VERSION 5.8 ;
BUSBITCHARS "[]" ;
DIVIDERCHAR "/" ;

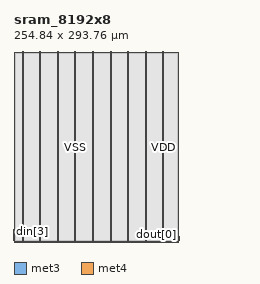
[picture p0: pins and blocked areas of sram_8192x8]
MACRO sram_8192x8
  CLASS BLOCK ;
  ORIGIN 0 0 ;
  SIZE 254.840 BY 293.760 ;
  SYMMETRY X Y ;

  PIN clk
    DIRECTION INPUT ;
    USE CLOCK ;
    PORT
      LAYER met3 ;
        RECT -0.500 2.890 0.500 3.230 ;
    END
  END clk

  PIN ce
    DIRECTION INPUT ;
    USE SIGNAL ;
    PORT
      LAYER met3 ;
        RECT -0.500 3.570 0.500 3.910 ;
    END
  END ce

  PIN we
    DIRECTION INPUT ;
    USE SIGNAL ;
    PORT
      LAYER met3 ;
        RECT -0.500 4.250 0.500 4.590 ;
    END
  END we

  PIN addr[0]
    DIRECTION INPUT ;
    USE SIGNAL ;
    PORT
      LAYER met3 ;
        RECT -0.500 4.930 0.500 5.270 ;
    END
  END addr[0]

  PIN addr[1]
    DIRECTION INPUT ;
    USE SIGNAL ;
    PORT
      LAYER met3 ;
        RECT -0.500 5.610 0.500 5.950 ;
    END
  END addr[1]

  PIN addr[2]
    DIRECTION INPUT ;
    USE SIGNAL ;
    PORT
      LAYER met3 ;
        RECT -0.500 6.290 0.500 6.630 ;
    END
  END addr[2]

  PIN addr[3]
    DIRECTION INPUT ;
    USE SIGNAL ;
    PORT
      LAYER met3 ;
        RECT -0.500 6.970 0.500 7.310 ;
    END
  END addr[3]

  PIN addr[4]
    DIRECTION INPUT ;
    USE SIGNAL ;
    PORT
      LAYER met3 ;
        RECT -0.500 7.650 0.500 7.990 ;
    END
  END addr[4]

  PIN addr[5]
    DIRECTION INPUT ;
    USE SIGNAL ;
    PORT
      LAYER met3 ;
        RECT -0.500 8.330 0.500 8.670 ;
    END
  END addr[5]

  PIN addr[6]
    DIRECTION INPUT ;
    USE SIGNAL ;
    PORT
      LAYER met3 ;
        RECT -0.500 9.010 0.500 9.350 ;
    END
  END addr[6]

  PIN addr[7]
    DIRECTION INPUT ;
    USE SIGNAL ;
    PORT
      LAYER met3 ;
        RECT -0.500 9.690 0.500 10.030 ;
    END
  END addr[7]

  PIN addr[8]
    DIRECTION INPUT ;
    USE SIGNAL ;
    PORT
      LAYER met3 ;
        RECT -0.500 10.370 0.500 10.710 ;
    END
  END addr[8]

  PIN addr[9]
    DIRECTION INPUT ;
    USE SIGNAL ;
    PORT
      LAYER met3 ;
        RECT -0.500 11.050 0.500 11.390 ;
    END
  END addr[9]

  PIN addr[10]
    DIRECTION INPUT ;
    USE SIGNAL ;
    PORT
      LAYER met3 ;
        RECT -0.500 11.730 0.500 12.070 ;
    END
  END addr[10]

  PIN addr[11]
    DIRECTION INPUT ;
    USE SIGNAL ;
    PORT
      LAYER met3 ;
        RECT -0.500 12.410 0.500 12.750 ;
    END
  END addr[11]

  PIN addr[12]
    DIRECTION INPUT ;
    USE SIGNAL ;
    PORT
      LAYER met3 ;
        RECT -0.500 13.090 0.500 13.430 ;
    END
  END addr[12]

  PIN din[0]
    DIRECTION INPUT ;
    USE SIGNAL ;
    PORT
      LAYER met3 ;
        RECT -0.500 13.770 0.500 14.110 ;
    END
  END din[0]

  PIN din[1]
    DIRECTION INPUT ;
    USE SIGNAL ;
    PORT
      LAYER met3 ;
        RECT -0.500 14.450 0.500 14.790 ;
    END
  END din[1]

  PIN din[2]
    DIRECTION INPUT ;
    USE SIGNAL ;
    PORT
      LAYER met3 ;
        RECT -0.500 15.130 0.500 15.470 ;
    END
  END din[2]

  PIN din[3]
    DIRECTION INPUT ;
    USE SIGNAL ;
    PORT
      LAYER met3 ;
        RECT -0.500 15.810 0.500 16.150 ;
    END
  END din[3]

  PIN din[4]
    DIRECTION INPUT ;
    USE SIGNAL ;
    PORT
      LAYER met3 ;
        RECT -0.500 16.490 0.500 16.830 ;
    END
  END din[4]

  PIN din[5]
    DIRECTION INPUT ;
    USE SIGNAL ;
    PORT
      LAYER met3 ;
        RECT -0.500 17.170 0.500 17.510 ;
    END
  END din[5]

  PIN din[6]
    DIRECTION INPUT ;
    USE SIGNAL ;
    PORT
      LAYER met3 ;
        RECT -0.500 17.850 0.500 18.190 ;
    END
  END din[6]

  PIN din[7]
    DIRECTION INPUT ;
    USE SIGNAL ;
    PORT
      LAYER met3 ;
        RECT -0.500 18.530 0.500 18.870 ;
    END
  END din[7]

  PIN dout[0]
    DIRECTION OUTPUT ;
    USE SIGNAL ;
    PORT
      LAYER met3 ;
        RECT 254.340 2.890 255.340 3.230 ;
    END
  END dout[0]

  PIN dout[1]
    DIRECTION OUTPUT ;
    USE SIGNAL ;
    PORT
      LAYER met3 ;
        RECT 254.340 3.570 255.340 3.910 ;
    END
  END dout[1]

  PIN dout[2]
    DIRECTION OUTPUT ;
    USE SIGNAL ;
    PORT
      LAYER met3 ;
        RECT 254.340 4.250 255.340 4.590 ;
    END
  END dout[2]

  PIN dout[3]
    DIRECTION OUTPUT ;
    USE SIGNAL ;
    PORT
      LAYER met3 ;
        RECT 254.340 4.930 255.340 5.270 ;
    END
  END dout[3]

  PIN dout[4]
    DIRECTION OUTPUT ;
    USE SIGNAL ;
    PORT
      LAYER met3 ;
        RECT 254.340 5.610 255.340 5.950 ;
    END
  END dout[4]

  PIN dout[5]
    DIRECTION OUTPUT ;
    USE SIGNAL ;
    PORT
      LAYER met3 ;
        RECT 254.340 6.290 255.340 6.630 ;
    END
  END dout[5]

  PIN dout[6]
    DIRECTION OUTPUT ;
    USE SIGNAL ;
    PORT
      LAYER met3 ;
        RECT 254.340 6.970 255.340 7.310 ;
    END
  END dout[6]

  PIN dout[7]
    DIRECTION OUTPUT ;
    USE SIGNAL ;
    PORT
      LAYER met3 ;
        RECT 254.340 7.650 255.340 7.990 ;
    END
  END dout[7]

  PIN VDD
    DIRECTION INOUT ;
    USE POWER ;
    PORT
      LAYER met4 ;
        RECT 12.770 0.000 14.370 293.760 ;
        RECT 67.050 0.000 68.650 293.760 ;
        RECT 121.330 0.000 122.930 293.760 ;
        RECT 175.610 0.000 177.210 293.760 ;
        RECT 229.890 0.000 231.490 293.760 ;
    END
  END VDD

  PIN VSS
    DIRECTION INOUT ;
    USE GROUND ;
    PORT
      LAYER met4 ;
        RECT 39.910 0.000 41.510 293.760 ;
        RECT 94.190 0.000 95.790 293.760 ;
        RECT 148.470 0.000 150.070 293.760 ;
        RECT 202.750 0.000 204.350 293.760 ;
    END
  END VSS

  OBS
    LAYER met1 ;
      RECT 2.000 2.000 252.840 291.760 ;
    LAYER met2 ;
      RECT 2.000 2.000 252.840 291.760 ;
    LAYER met4 ;
      RECT 2.000 2.000 252.840 291.760 ;
  END

END sram_8192x8

END LIBRARY
